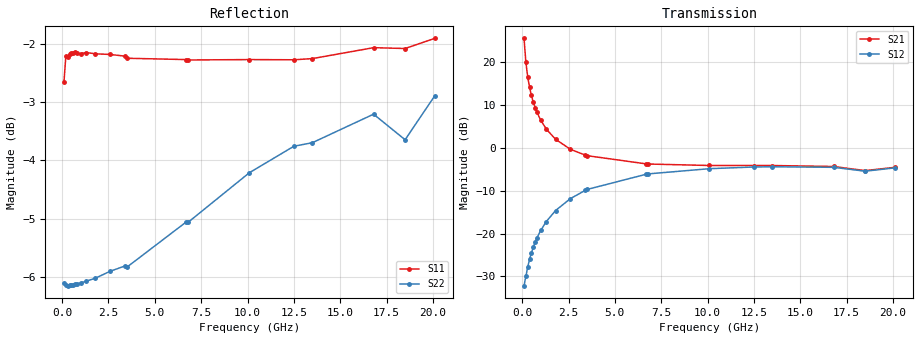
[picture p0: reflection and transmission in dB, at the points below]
!  Infineon Technologies AG
! BFR380L3 , PF131585-7, No.6, Th 09.10.01, soldered on pcb-board, measured with PP GSG850
!  Vce=0.5 V,  Ic=60.0 mA
! Common Emitter S-Parameters:  15. November 2001
#  GHz  S  MA  R  50
! f  S11  S21  S12  S22
! GHz  Mag  Ang  Mag  Ang  Mag  Ang  Mag  Ang
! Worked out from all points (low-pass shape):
!   201 points, 100 MHz to 20.1 GHz, reference 50 ohm
!   highest |S21| = 25.56 dB at 100 MHz (marker M1); lowest = -5.3 dB at 18.5 GHz (marker M2)
!   |S21| within 3 dB of the highest: start of sweep to 153.7 MHz
!   lowest |S11| = -2.7 dB at 100 MHz (marker M3), VSWR 6.60, Z = 7.92 - j10.5 ohm
!   |S11| at or under -10 dB: nowhere
!   |S22| runs from -6.2 to -2.9 dB; largest |S21 - S12| = 19
!   S11 on the Smith chart (normalised r, x): 100 MHz: 0.16, -0.21; 1 GHz: 0.13, +0.11; 3.4 GHz: 0.15, +0.45; 6.7 GHz: 0.24, +0.89; 12.5 GHz: 0.49, +1.61; 20.1 GHz: 0.98, +2.66
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0.1  0.7367 -155.8  18.96 108.0  0.02464 41.9  0.495 -140.1
0.2  0.7745 -169.5  9.974 96.2  0.03176 50.5  0.4937 -160.5
0.3  0.7739 -175.6  6.732 91.3  0.04064 56.5  0.4926 -168.4
0.4  0.7779 -179.4  5.083 87.7  0.05015 60.8  0.4929 -172.9
0.5  0.7789 177.8  4.087 84.8  0.0596 63.4  0.4934 -175.9
0.6  0.7794 175.2  3.421 82.3  0.0695 64.9  0.4937 -178.3
0.7  0.781 172.9  2.949 79.9  0.07905 65.8  0.4942 179.8
0.8  0.7794 170.9  2.598 77.7  0.08913 66.3  0.4943 178.1
1  0.7787 167.1  2.109 73.7  0.1088 66.4  0.4953 175.1
1.3  0.7804 161.9  1.66 67.9  0.138 65.3  0.497 171.3
1.8  0.7784 153.8  1.26 59.4  0.1855 62.2  0.5 165.8
2.6  0.7774 141.9  0.9627 47.6  0.2555 55.6  0.5069 157.8
3.4  0.7748 130.8  0.8238 37.9  0.3191 48.5  0.5122 150.0
3.5  0.7716 129.4  0.8109 36.7  0.327 47.6  0.511 149.3
6.7  0.7696 95.1  0.6499 11.4  0.4929 21.7  0.5587 122.1
6.8  0.769 94.2  0.6478 10.7  0.497 20.9  0.5583 121.2
10.1  0.7696 71.6  0.6227 -5.9  0.5715 0.2  0.6156 99.5
12.5  0.7693 60.2  0.6225 -16.7  0.598 -12.7  0.6486 84.8
13.5  0.7711 56.2  0.6224 -21.1  0.6016 -17.7  0.6532 79.7
16.8  0.7879 45.6  0.6063 -32.7  0.593 -30.8  0.691 64.5
18.5  0.7866 43.7  0.5429 -40.0  0.5339 -38.3  0.657 61.1
20.1  0.8025 37.1  0.5925 -43.9  0.5837 -42.5  0.7165 51.9
